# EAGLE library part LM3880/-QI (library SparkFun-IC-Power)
LM3880 Simple Power Sequencer Precision enable pin & 3 open-drain output flags Input Voltage Range of 2.7 V to 5.5 V Power-Up and Power-Down Control The timing sequence of the LM3880 is controlled entirely by the enable (EN) pin. Upon power up, all the flags are held low until this precision enable is pulled high LM3880MF-1XY (Timing Designator) AF: 16ms AE: 2ms AA: 10ms AB: 30ms AC: 60ms AD: 120ms SparkFun Products SparkFun 6 Degrees of Freedom Breakout - LSM303C (BOB-13303)

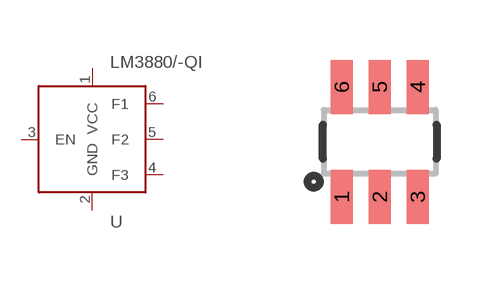
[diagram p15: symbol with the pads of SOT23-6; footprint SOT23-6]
Designator prefix U

## LM3880/-QI (PROD_ID: IC-12558; VALUE: LM3880)  [SOT23-6]
1  VCC
2  GND
3  EN
4  F3
5  F2
6  F1

## Footprint SOT23-6 (pad centres in mm)
SOT23 (6 pin) Mechanical Layout Landing Pad: 0.55mm X 1.395mm Landing Pad Pitch: 0.95mm 2.7mm vertical distance between pads
smd 0.55 x 1.35: 1 -0.95,-1.375; 2 0,-1.375; 3 0.95,-1.375; 4 0.95,1.375; 5 0,1.375; 6 -0.95,1.375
